VERSION 5.8 ;
BUSBITCHARS "[]" ;
DIVIDERCHAR "/" ;
UNITS
    DATABASE MICRONS 1000 ;
END UNITS

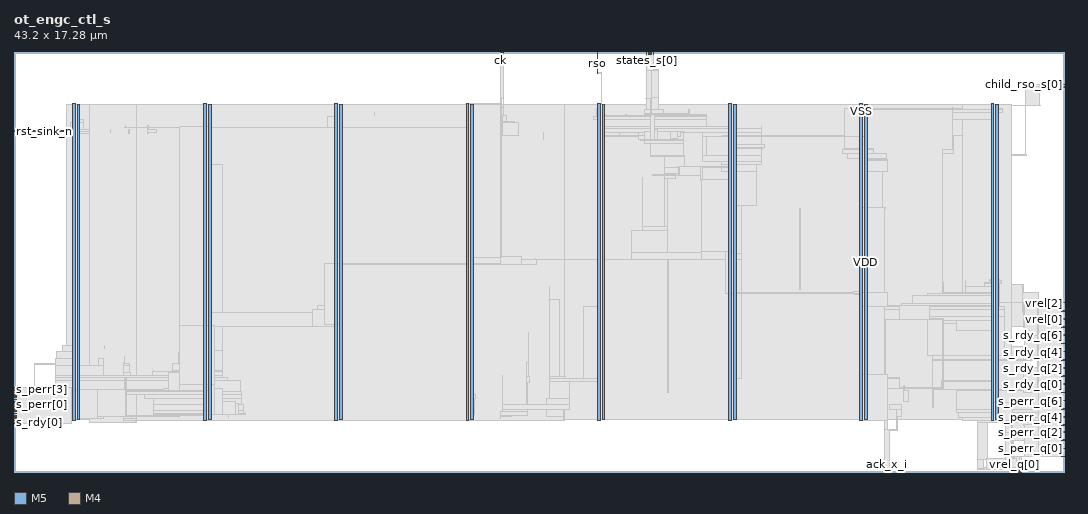
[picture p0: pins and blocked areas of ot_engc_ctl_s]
MACRO ot_engc_ctl_s
  FOREIGN ot_engc_ctl_s 0 0 ;
  CLASS BLOCK ;
  SIZE 43.2 BY 17.28 ;
  PIN ack_x_i
    DIRECTION INPUT ;
    USE SIGNAL ;
    PORT
      LAYER M5 ;
        RECT  35.904 0 35.928 0.084 ;
    END
  END ack_x_i
  PIN child_rso_s[0]
    DIRECTION INPUT ;
    USE SIGNAL ;
    PORT
      LAYER M4 ;
        RECT  43.116 15.936 43.2 15.96 ;
    END
  END child_rso_s[0]
  PIN child_rso_s[1]
    DIRECTION INPUT ;
    USE SIGNAL ;
    PORT
      LAYER M5 ;
        RECT  35.808 0 35.832 0.084 ;
    END
  END child_rso_s[1]
  PIN ck
    DIRECTION INPUT ;
    USE SIGNAL ;
    PORT
      LAYER M5 ;
        RECT  20.016 17.196 20.04 17.28 ;
    END
  END ck
  PIN rso
    DIRECTION OUTPUT ;
    USE SIGNAL ;
    PORT
      LAYER M5 ;
        RECT  24 17.196 24.024 17.28 ;
    END
    PORT
      LAYER M5 ;
        RECT  24 16.405 24.024 17.232 ;
    END
  END rso
  PIN rst
    DIRECTION INPUT ;
    USE SIGNAL ;
    PORT
      LAYER M5 ;
        RECT  20.112 17.196 20.136 17.28 ;
    END
  END rst
  PIN rst_lkp_n
    DIRECTION OUTPUT ;
    USE SIGNAL ;
    PORT
      LAYER M5 ;
        RECT  41.04 0 41.064 0.084 ;
    END
  END rst_lkp_n
  PIN rst_sink_n
    DIRECTION OUTPUT ;
    USE SIGNAL ;
    PORT
      LAYER M4 ;
        RECT  0 14.016 0.084 14.04 ;
    END
    PORT
      LAYER M4 ;
        RECT  0.06 14.016 2.408 14.04 ;
    END
  END rst_sink_n
  PIN rst_win_n
    DIRECTION OUTPUT ;
    USE SIGNAL ;
    PORT
      LAYER M4 ;
        RECT  43.116 15.84 43.2 15.864 ;
    END
  END rst_win_n
  PIN rst_ws_n
    DIRECTION OUTPUT ;
    USE SIGNAL ;
    PORT
      LAYER M5 ;
        RECT  36 0 36.024 0.084 ;
    END
  END rst_ws_n
  PIN s_perr[0]
    DIRECTION INPUT ;
    USE SIGNAL ;
    PORT
      LAYER M4 ;
        RECT  0 2.784 0.084 2.808 ;
    END
  END s_perr[0]
  PIN s_perr[1]
    DIRECTION INPUT ;
    USE SIGNAL ;
    PORT
      LAYER M4 ;
        RECT  0 2.88 0.084 2.904 ;
    END
  END s_perr[1]
  PIN s_perr[2]
    DIRECTION INPUT ;
    USE SIGNAL ;
    PORT
      LAYER M4 ;
        RECT  0 2.976 0.084 3 ;
    END
  END s_perr[2]
  PIN s_perr[3]
    DIRECTION INPUT ;
    USE SIGNAL ;
    PORT
      LAYER M4 ;
        RECT  0 3.072 0.084 3.096 ;
    END
  END s_perr[3]
  PIN s_perr[4]
    DIRECTION INPUT ;
    USE SIGNAL ;
    PORT
      LAYER M4 ;
        RECT  0 3.168 0.084 3.192 ;
    END
  END s_perr[4]
  PIN s_perr[5]
    DIRECTION INPUT ;
    USE SIGNAL ;
    PORT
      LAYER M4 ;
        RECT  0 3.264 0.084 3.288 ;
    END
  END s_perr[5]
  PIN s_perr[6]
    DIRECTION INPUT ;
    USE SIGNAL ;
    PORT
      LAYER M4 ;
        RECT  0 3.36 0.084 3.384 ;
    END
  END s_perr[6]
  PIN s_perr[7]
    DIRECTION INPUT ;
    USE SIGNAL ;
    PORT
      LAYER M4 ;
        RECT  0 3.456 0.084 3.48 ;
    END
  END s_perr[7]
  PIN s_perr_q[0]
    DIRECTION OUTPUT ;
    USE SIGNAL ;
    PORT
      LAYER M4 ;
        RECT  43.116 0.624 43.2 0.648 ;
    END
  END s_perr_q[0]
  PIN s_perr_q[1]
    DIRECTION OUTPUT ;
    USE SIGNAL ;
    PORT
      LAYER M4 ;
        RECT  43.116 0.96 43.2 0.984 ;
    END
  END s_perr_q[1]
  PIN s_perr_q[2]
    DIRECTION OUTPUT ;
    USE SIGNAL ;
    PORT
      LAYER M4 ;
        RECT  43.116 1.296 43.2 1.32 ;
    END
  END s_perr_q[2]
  PIN s_perr_q[3]
    DIRECTION OUTPUT ;
    USE SIGNAL ;
    PORT
      LAYER M4 ;
        RECT  43.116 1.632 43.2 1.656 ;
    END
  END s_perr_q[3]
  PIN s_perr_q[4]
    DIRECTION OUTPUT ;
    USE SIGNAL ;
    PORT
      LAYER M4 ;
        RECT  43.116 1.92 43.2 1.944 ;
    END
  END s_perr_q[4]
  PIN s_perr_q[5]
    DIRECTION OUTPUT ;
    USE SIGNAL ;
    PORT
      LAYER M4 ;
        RECT  43.116 2.256 43.2 2.28 ;
    END
  END s_perr_q[5]
  PIN s_perr_q[6]
    DIRECTION OUTPUT ;
    USE SIGNAL ;
    PORT
      LAYER M4 ;
        RECT  43.116 2.592 43.2 2.616 ;
    END
  END s_perr_q[6]
  PIN s_perr_q[7]
    DIRECTION OUTPUT ;
    USE SIGNAL ;
    PORT
      LAYER M4 ;
        RECT  43.116 2.928 43.2 2.952 ;
    END
  END s_perr_q[7]
  PIN s_rdy[0]
    DIRECTION INPUT ;
    USE SIGNAL ;
    PORT
      LAYER M4 ;
        RECT  0 2.016 0.084 2.04 ;
    END
  END s_rdy[0]
  PIN s_rdy[1]
    DIRECTION INPUT ;
    USE SIGNAL ;
    PORT
      LAYER M4 ;
        RECT  0 2.112 0.084 2.136 ;
    END
  END s_rdy[1]
  PIN s_rdy[2]
    DIRECTION INPUT ;
    USE SIGNAL ;
    PORT
      LAYER M4 ;
        RECT  0 2.208 0.084 2.232 ;
    END
  END s_rdy[2]
  PIN s_rdy[3]
    DIRECTION INPUT ;
    USE SIGNAL ;
    PORT
      LAYER M4 ;
        RECT  0 2.304 0.084 2.328 ;
    END
  END s_rdy[3]
  PIN s_rdy[4]
    DIRECTION INPUT ;
    USE SIGNAL ;
    PORT
      LAYER M4 ;
        RECT  0 2.4 0.084 2.424 ;
    END
  END s_rdy[4]
  PIN s_rdy[5]
    DIRECTION INPUT ;
    USE SIGNAL ;
    PORT
      LAYER M4 ;
        RECT  0 2.496 0.084 2.52 ;
    END
  END s_rdy[5]
  PIN s_rdy[6]
    DIRECTION INPUT ;
    USE SIGNAL ;
    PORT
      LAYER M4 ;
        RECT  0 2.592 0.084 2.616 ;
    END
  END s_rdy[6]
  PIN s_rdy[7]
    DIRECTION INPUT ;
    USE SIGNAL ;
    PORT
      LAYER M4 ;
        RECT  0 2.688 0.084 2.712 ;
    END
  END s_rdy[7]
  PIN s_rdy_q[0]
    DIRECTION OUTPUT ;
    USE SIGNAL ;
    PORT
      LAYER M4 ;
        RECT  43.116 3.264 43.2 3.288 ;
    END
  END s_rdy_q[0]
  PIN s_rdy_q[1]
    DIRECTION OUTPUT ;
    USE SIGNAL ;
    PORT
      LAYER M4 ;
        RECT  43.116 3.6 43.2 3.624 ;
    END
  END s_rdy_q[1]
  PIN s_rdy_q[2]
    DIRECTION OUTPUT ;
    USE SIGNAL ;
    PORT
      LAYER M4 ;
        RECT  43.116 3.936 43.2 3.96 ;
    END
  END s_rdy_q[2]
  PIN s_rdy_q[3]
    DIRECTION OUTPUT ;
    USE SIGNAL ;
    PORT
      LAYER M4 ;
        RECT  43.116 4.272 43.2 4.296 ;
    END
  END s_rdy_q[3]
  PIN s_rdy_q[4]
    DIRECTION OUTPUT ;
    USE SIGNAL ;
    PORT
      LAYER M4 ;
        RECT  43.116 4.608 43.2 4.632 ;
    END
  END s_rdy_q[4]
  PIN s_rdy_q[5]
    DIRECTION OUTPUT ;
    USE SIGNAL ;
    PORT
      LAYER M4 ;
        RECT  43.116 4.944 43.2 4.968 ;
    END
  END s_rdy_q[5]
  PIN s_rdy_q[6]
    DIRECTION OUTPUT ;
    USE SIGNAL ;
    PORT
      LAYER M4 ;
        RECT  43.116 5.28 43.2 5.304 ;
    END
  END s_rdy_q[6]
  PIN s_rdy_q[7]
    DIRECTION OUTPUT ;
    USE SIGNAL ;
    PORT
      LAYER M4 ;
        RECT  43.116 5.616 43.2 5.64 ;
    END
  END s_rdy_q[7]
  PIN states_s[0]
    DIRECTION OUTPUT ;
    USE SIGNAL ;
    PORT
      LAYER M5 ;
        RECT  26.016 17.196 26.04 17.28 ;
    END
  END states_s[0]
  PIN states_s[1]
    DIRECTION OUTPUT ;
    USE SIGNAL ;
    PORT
      LAYER M5 ;
        RECT  26.112 17.196 26.136 17.28 ;
    END
  END states_s[1]
  PIN states_s[2]
    DIRECTION OUTPUT ;
    USE SIGNAL ;
    PORT
      LAYER M5 ;
        RECT  26.208 17.196 26.232 17.28 ;
    END
  END states_s[2]
  PIN states_s[3]
    DIRECTION OUTPUT ;
    USE SIGNAL ;
    PORT
      LAYER M5 ;
        RECT  26.304 17.196 26.328 17.28 ;
    END
  END states_s[3]
  PIN vrel[0]
    DIRECTION INPUT ;
    USE SIGNAL ;
    PORT
      LAYER M4 ;
        RECT  43.116 5.952 43.2 5.976 ;
    END
  END vrel[0]
  PIN vrel[1]
    DIRECTION INPUT ;
    USE SIGNAL ;
    PORT
      LAYER M4 ;
        RECT  43.116 6.288 43.2 6.312 ;
    END
  END vrel[1]
  PIN vrel[2]
    DIRECTION INPUT ;
    USE SIGNAL ;
    PORT
      LAYER M4 ;
        RECT  43.116 6.624 43.2 6.648 ;
    END
  END vrel[2]
  PIN vrel[3]
    DIRECTION INPUT ;
    USE SIGNAL ;
    PORT
      LAYER M4 ;
        RECT  43.116 6.96 43.2 6.984 ;
    END
  END vrel[3]
  PIN vrel_q[0]
    DIRECTION OUTPUT ;
    USE SIGNAL ;
    PORT
      LAYER M5 ;
        RECT  41.136 0 41.16 0.084 ;
    END
  END vrel_q[0]
  PIN vrel_q[1]
    DIRECTION OUTPUT ;
    USE SIGNAL ;
    PORT
      LAYER M5 ;
        RECT  41.232 0 41.256 0.084 ;
    END
  END vrel_q[1]
  PIN vrel_q[2]
    DIRECTION OUTPUT ;
    USE SIGNAL ;
    PORT
      LAYER M5 ;
        RECT  41.328 0 41.352 0.084 ;
    END
  END vrel_q[2]
  PIN vrel_q[3]
    DIRECTION OUTPUT ;
    USE SIGNAL ;
    PORT
      LAYER M5 ;
        RECT  41.424 0 41.448 0.084 ;
    END
  END vrel_q[3]
  PIN VDD
    DIRECTION INOUT ;
    USE POWER ;
    PORT
      LAYER M5 ;
        RECT  40.392 2.151 40.512 15.129 ;
        RECT  34.992 2.151 35.112 15.129 ;
        RECT  29.592 2.151 29.712 15.129 ;
        RECT  24.192 2.151 24.312 15.129 ;
        RECT  18.792 2.151 18.912 15.129 ;
        RECT  13.392 2.151 13.512 15.129 ;
        RECT  7.992 2.151 8.112 15.129 ;
        RECT  2.592 2.151 2.712 15.129 ;
    END
  END VDD
  PIN VSS
    DIRECTION INOUT ;
    USE GROUND ;
    PORT
      LAYER M5 ;
        RECT  40.2 2.137 40.32 15.143 ;
        RECT  34.8 2.137 34.92 15.143 ;
        RECT  29.4 2.137 29.52 15.143 ;
        RECT  24 2.137 24.12 15.143 ;
        RECT  18.6 2.137 18.72 15.143 ;
        RECT  13.2 2.137 13.32 15.143 ;
        RECT  7.8 2.137 7.92 15.143 ;
        RECT  2.4 2.137 2.52 15.143 ;
    END
  END VSS
  # OT_OBS_CLOSED layer=M5 d_um=1.536 added=5
  OBS
    LAYER RVTN ;
     RECT  2.16 2.16 41.04 2.295 ;
     RECT  2.16 2.565 41.04 2.835 ;
     RECT  2.16 3.105 41.04 3.375 ;
     RECT  2.16 3.645 41.04 3.915 ;
     RECT  2.16 4.185 41.04 4.455 ;
     RECT  2.16 4.725 41.04 4.995 ;
     RECT  2.16 5.265 41.04 5.535 ;
     RECT  2.16 5.805 41.04 6.075 ;
     RECT  2.16 6.345 41.04 6.615 ;
     RECT  2.16 6.885 41.04 7.155 ;
     RECT  2.16 7.425 41.04 7.695 ;
     RECT  2.16 7.965 41.04 8.235 ;
     RECT  2.16 8.505 41.04 8.775 ;
     RECT  2.16 9.045 41.04 9.315 ;
     RECT  2.16 9.585 41.04 9.855 ;
     RECT  2.16 10.125 41.04 10.395 ;
     RECT  2.16 10.665 41.04 10.935 ;
     RECT  2.16 11.205 41.04 11.475 ;
     RECT  2.16 11.745 41.04 12.015 ;
     RECT  2.16 12.285 41.04 12.555 ;
     RECT  2.16 12.825 41.04 13.095 ;
     RECT  2.16 13.365 41.04 13.635 ;
     RECT  2.16 13.905 41.04 14.175 ;
     RECT  2.16 14.445 41.04 14.715 ;
     RECT  2.16 14.985 41.04 15.12 ;
    LAYER RVTP ;
     RECT  2.16 2.295 41.04 2.565 ;
     RECT  2.16 2.835 41.04 3.105 ;
     RECT  2.16 3.375 41.04 3.645 ;
     RECT  2.16 3.915 41.04 4.185 ;
     RECT  2.16 4.455 41.04 4.725 ;
     RECT  2.16 4.995 41.04 5.265 ;
     RECT  2.16 5.535 41.04 5.805 ;
     RECT  2.16 6.075 41.04 6.345 ;
     RECT  2.16 6.615 41.04 6.885 ;
     RECT  2.16 7.155 41.04 7.425 ;
     RECT  2.16 7.695 41.04 7.965 ;
     RECT  2.16 8.235 41.04 8.505 ;
     RECT  2.16 8.775 41.04 9.045 ;
     RECT  2.16 9.315 41.04 9.585 ;
     RECT  2.16 9.855 41.04 10.125 ;
     RECT  2.16 10.395 41.04 10.665 ;
     RECT  2.16 10.935 41.04 11.205 ;
     RECT  2.16 11.475 41.04 11.745 ;
     RECT  2.16 12.015 41.04 12.285 ;
     RECT  2.16 12.555 41.04 12.825 ;
     RECT  2.16 13.095 41.04 13.365 ;
     RECT  2.16 13.635 41.04 13.905 ;
     RECT  2.16 14.175 41.04 14.445 ;
     RECT  2.16 14.715 41.04 14.985 ;
    LAYER M1 ;
     RECT  2.16 2.151 41.04 15.129 ;
    LAYER M2 ;
     RECT  0.823 4.428 1.723 4.446 ;
     RECT  1.723 4.428 1.759 4.68 ;
     RECT  1.759 4.428 1.975 4.95 ;
     RECT  1.975 4.428 2.16 5.22 ;
     RECT  2.16 2.151 3.091 15.129 ;
     RECT  3.091 2.034 5.027 15.129 ;
     RECT  5.027 2.106 22.631 15.129 ;
     RECT  22.631 2.151 39.019 15.129 ;
     RECT  39.019 2.106 40.387 15.129 ;
     RECT  40.387 2.034 41.04 15.129 ;
     RECT  41.04 5.976 41.531 7.722 ;
     RECT  41.04 2.034 41.567 5.184 ;
     RECT  41.567 2.034 41.603 3.366 ;
     RECT  41.567 4.896 41.603 5.184 ;
     RECT  41.531 5.976 41.603 7.38 ;
     RECT  41.04 13.032 41.639 13.05 ;
     RECT  41.603 5.976 42.143 6.534 ;
     RECT  41.603 7.362 42.143 7.38 ;
     RECT  41.603 2.268 42.179 3.366 ;
     RECT  41.603 5.166 42.179 5.184 ;
     RECT  42.143 6.516 42.179 6.534 ;
     RECT  42.179 3.348 42.215 3.366 ;
     RECT  41.04 15.066 42.215 15.084 ;
     RECT  42.179 2.538 42.251 2.556 ;
    LAYER M3 ;
     RECT  39.636 0.091 39.654 0.139 ;
     RECT  39.636 0.139 39.906 0.523 ;
     RECT  41.112 0.571 41.13 0.619 ;
     RECT  40.788 0.619 41.13 1.291 ;
     RECT  42.192 0.955 42.21 1.291 ;
     RECT  40.788 1.291 42.21 1.627 ;
     RECT  39.636 0.523 40.05 2.029 ;
     RECT  40.788 1.627 42.246 2.029 ;
     RECT  5.004 2.029 5.022 2.101 ;
     RECT  39.636 2.029 42.246 2.101 ;
     RECT  2.34 2.011 2.358 2.107 ;
     RECT  2.304 2.107 2.358 2.143 ;
     RECT  3.096 2.029 3.114 2.143 ;
     RECT  2.304 2.143 3.114 2.191 ;
     RECT  34.815 2.143 34.905 2.191 ;
     RECT  2.304 2.191 3.69 2.203 ;
     RECT  4.5 2.101 5.022 2.219 ;
     RECT  39.024 2.101 42.246 2.227 ;
     RECT  22.608 2.101 22.626 2.263 ;
     RECT  36.324 1.723 36.342 2.263 ;
     RECT  2.268 2.203 3.69 2.299 ;
     RECT  4.5 2.219 4.842 2.299 ;
     RECT  6.804 2.227 6.822 2.299 ;
     RECT  20.016 2.191 20.034 2.299 ;
     RECT  2.268 2.299 4.842 2.333 ;
     RECT  5.724 2.299 6.822 2.335 ;
     RECT  7.815 2.143 7.905 2.335 ;
     RECT  20.016 2.299 20.466 2.335 ;
     RECT  5.724 2.335 7.905 2.347 ;
     RECT  8.82 2.227 8.838 2.347 ;
     RECT  18.615 2.143 18.705 2.371 ;
     RECT  8.82 2.347 9.522 2.399 ;
     RECT  5.724 2.347 7.974 2.413 ;
     RECT  13.215 2.143 13.305 2.413 ;
     RECT  24.015 2.143 24.105 2.413 ;
     RECT  29.415 2.143 29.505 2.413 ;
     RECT  34.776 2.191 34.905 2.413 ;
     RECT  38.844 2.227 42.246 2.461 ;
     RECT  20.016 2.335 21.114 2.489 ;
     RECT  5.724 2.413 8.097 2.533 ;
     RECT  8.82 2.399 9.45 2.533 ;
     RECT  38.772 2.461 42.246 2.561 ;
     RECT  20.088 2.489 21.114 2.569 ;
     RECT  21.924 2.263 22.626 2.569 ;
     RECT  36.324 2.263 36.522 2.569 ;
     RECT  34.776 2.413 35.097 2.633 ;
     RECT  2.268 2.333 4.194 2.683 ;
     RECT  5.724 2.533 9.45 2.759 ;
     RECT  20.088 2.569 22.842 2.759 ;
     RECT  36.036 2.569 36.522 2.795 ;
     RECT  1.98 2.683 4.194 2.971 ;
     RECT  21.924 2.759 22.842 3.029 ;
     RECT  5.724 2.759 9.342 3.037 ;
     RECT  18.615 2.371 18.954 3.037 ;
     RECT  1.728 2.971 4.194 3.181 ;
     RECT  5.364 3.037 9.342 3.181 ;
     RECT  18.615 3.037 18.99 3.209 ;
     RECT  1.728 3.181 9.342 3.299 ;
     RECT  36.612 2.911 36.81 3.335 ;
     RECT  38.772 2.561 42.21 3.371 ;
     RECT  37.8 2.641 37.818 3.379 ;
     RECT  38.772 3.371 41.598 3.379 ;
     RECT  34.815 2.633 35.097 3.451 ;
     RECT  36.612 3.335 36.63 3.569 ;
     RECT  34.815 3.451 35.37 3.577 ;
     RECT  21.096 2.759 21.114 3.685 ;
     RECT  22.032 3.029 22.842 3.721 ;
     RECT  24.015 2.413 24.297 3.721 ;
     RECT  34.815 3.577 36.414 3.721 ;
     RECT  1.728 3.299 9.306 3.749 ;
     RECT  22.032 3.721 24.297 3.839 ;
     RECT  29.415 2.413 29.697 3.847 ;
     RECT  34.776 3.721 36.414 3.869 ;
     RECT  1.728 3.749 8.802 3.875 ;
     RECT  34.776 3.869 36.342 3.875 ;
     RECT  21.096 3.685 21.222 3.911 ;
     RECT  22.032 3.839 22.698 3.947 ;
     RECT  34.776 3.875 35.838 3.947 ;
     RECT  1.728 3.875 8.586 3.983 ;
     RECT  20.088 2.759 20.106 3.983 ;
     RECT  4.5 3.983 4.806 4.109 ;
     RECT  5.688 3.983 8.586 4.115 ;
     RECT  5.688 4.115 5.742 4.145 ;
     RECT  5.724 4.145 5.742 4.181 ;
     RECT  6.516 4.115 8.586 4.181 ;
     RECT  1.728 3.983 3.69 4.379 ;
     RECT  4.5 4.109 4.77 4.379 ;
     RECT  0.828 2.491 0.846 4.451 ;
     RECT  4.5 4.379 4.734 4.451 ;
     RECT  6.516 4.181 6.822 4.451 ;
     RECT  4.5 4.451 4.554 4.487 ;
     RECT  21.096 3.911 21.186 4.487 ;
     RECT  37.8 3.379 41.598 4.603 ;
     RECT  37.8 4.603 42.174 4.649 ;
     RECT  1.728 4.379 2.697 4.685 ;
     RECT  3.492 4.379 3.69 4.685 ;
     RECT  4.536 4.487 4.554 4.757 ;
     RECT  41.544 4.649 42.174 4.757 ;
     RECT  37.8 4.649 40.77 4.801 ;
     RECT  6.768 4.451 6.822 4.919 ;
     RECT  1.764 4.685 2.697 4.955 ;
     RECT  7.56 4.181 8.586 4.991 ;
     RECT  6.804 4.919 6.822 5.063 ;
     RECT  3.708 5.071 3.726 5.189 ;
     RECT  1.98 4.955 2.697 5.225 ;
     RECT  21.168 4.487 21.186 5.729 ;
     RECT  41.58 4.757 42.174 5.947 ;
     RECT  13.215 2.413 13.497 5.971 ;
     RECT  12.852 5.971 13.497 6.079 ;
     RECT  34.815 3.947 35.838 6.283 ;
     RECT  37.584 4.801 40.77 6.385 ;
     RECT  12.672 6.079 13.497 6.511 ;
     RECT  41.544 5.947 42.174 6.539 ;
     RECT  41.544 6.539 42.138 6.619 ;
     RECT  12.492 6.511 13.497 6.655 ;
     RECT  34.815 6.283 36.45 6.691 ;
     RECT  37.224 6.385 40.77 6.691 ;
     RECT  12.276 6.655 13.497 6.701 ;
     RECT  23.436 3.839 24.297 6.809 ;
     RECT  34.815 6.691 40.77 6.809 ;
     RECT  12.492 6.701 13.497 6.845 ;
     RECT  34.815 6.809 40.554 6.845 ;
     RECT  36.504 6.845 40.554 6.917 ;
     RECT  41.508 6.619 42.138 6.955 ;
     RECT  22.032 3.947 22.446 7.079 ;
     RECT  34.815 6.845 35.73 7.159 ;
     RECT  36.972 6.917 40.554 7.259 ;
     RECT  34.812 7.159 35.73 7.321 ;
     RECT  37.584 7.259 40.554 7.349 ;
     RECT  38.196 7.349 40.554 7.385 ;
     RECT  41.472 6.955 42.138 7.385 ;
     RECT  34.56 7.321 35.73 7.421 ;
     RECT  22.032 7.079 22.05 7.619 ;
     RECT  39.132 7.385 40.554 7.619 ;
     RECT  41.472 7.385 41.526 7.691 ;
     RECT  41.508 7.691 41.526 7.727 ;
     RECT  39.924 7.619 40.554 7.771 ;
     RECT  38.196 7.385 38.25 7.799 ;
     RECT  39.924 7.771 40.626 7.799 ;
     RECT  39.132 7.619 39.15 7.889 ;
     RECT  40.14 7.799 40.626 7.889 ;
     RECT  40.14 7.889 40.554 7.925 ;
     RECT  29.415 3.847 29.934 8.731 ;
     RECT  21.456 8.539 21.474 8.765 ;
     RECT  26.892 3.271 26.91 8.851 ;
     RECT  20.844 8.815 20.862 8.861 ;
     RECT  25.56 8.851 26.91 8.969 ;
     RECT  25.56 8.969 26.874 8.977 ;
     RECT  29.34 8.731 29.934 9.005 ;
     RECT  25.416 8.977 26.874 9.923 ;
     RECT  25.848 9.923 26.874 10.085 ;
     RECT  32.328 7.501 32.346 10.859 ;
     RECT  29.415 9.005 29.934 10.975 ;
     RECT  26.748 10.085 26.874 12.091 ;
     RECT  25.848 10.085 25.866 12.119 ;
     RECT  26.748 12.091 27.234 12.187 ;
     RECT  26.28 12.187 27.234 12.245 ;
     RECT  26.748 12.245 27.234 12.289 ;
     RECT  28.26 11.995 28.278 12.289 ;
     RECT  29.415 10.975 30.546 12.361 ;
     RECT  34.815 7.421 35.73 12.361 ;
     RECT  26.748 12.289 28.278 12.515 ;
     RECT  29.088 12.361 30.546 12.631 ;
     RECT  7.815 4.991 8.586 12.659 ;
     RECT  29.088 12.631 30.762 12.793 ;
     RECT  34.815 12.361 35.946 12.829 ;
     RECT  34.776 12.829 35.946 12.857 ;
     RECT  34.776 12.857 35.91 12.901 ;
     RECT  26.748 12.515 27.594 12.991 ;
     RECT  26.208 12.991 27.594 13.019 ;
     RECT  28.332 12.793 30.762 13.019 ;
     RECT  34.308 12.901 35.91 13.091 ;
     RECT  34.308 13.091 35.37 13.099 ;
     RECT  38.196 7.799 38.214 13.099 ;
     RECT  34.092 13.099 35.37 13.289 ;
     RECT  38.196 13.099 38.646 13.289 ;
     RECT  29.415 13.019 30.762 13.297 ;
     RECT  34.164 13.289 35.37 13.325 ;
     RECT  29.415 13.297 30.798 13.333 ;
     RECT  29.415 13.333 30.87 13.469 ;
     RECT  26.208 13.019 27.558 13.531 ;
     RECT  25.956 13.531 27.558 13.639 ;
     RECT  25.776 13.639 27.558 13.675 ;
     RECT  28.332 13.019 28.494 13.801 ;
     RECT  29.415 13.469 30.762 13.801 ;
     RECT  24.015 6.809 24.297 13.819 ;
     RECT  24.015 13.819 24.498 13.837 ;
     RECT  38.628 13.289 38.646 13.837 ;
     RECT  34.164 13.325 35.097 13.853 ;
     RECT  2.415 5.225 2.697 13.945 ;
     RECT  25.704 13.675 27.558 13.963 ;
     RECT  21.78 13.675 21.798 13.973 ;
     RECT  5.508 13.945 5.526 13.981 ;
     RECT  24.015 13.837 24.894 13.981 ;
     RECT  25.704 13.963 27.594 13.981 ;
     RECT  28.332 13.801 30.762 13.981 ;
     RECT  2.415 13.945 3.114 14.011 ;
     RECT  2.304 14.011 3.114 14.099 ;
     RECT  3.96 13.981 3.978 14.099 ;
     RECT  4.716 13.909 4.734 14.099 ;
     RECT  5.508 13.981 5.85 14.099 ;
     RECT  24.015 13.981 30.762 14.135 ;
     RECT  18.615 3.209 18.897 14.143 ;
     RECT  13.215 6.845 13.497 14.179 ;
     RECT  24.015 14.135 29.697 14.207 ;
     RECT  30.744 14.135 30.762 14.207 ;
     RECT  4.572 14.155 4.59 14.243 ;
     RECT  5.508 14.099 5.526 14.243 ;
     RECT  2.304 14.099 2.862 14.369 ;
     RECT  20.088 13.837 20.754 14.369 ;
     RECT  20.088 14.369 20.61 14.405 ;
     RECT  38.628 13.837 39.042 14.485 ;
     RECT  40.215 7.925 40.497 14.485 ;
     RECT  2.415 14.369 2.862 14.513 ;
     RECT  24.015 14.207 28.494 14.521 ;
     RECT  12.888 14.179 13.497 14.639 ;
     RECT  23.832 14.521 28.494 14.639 ;
     RECT  18.615 14.143 19.314 14.647 ;
     RECT  20.088 14.405 20.25 14.647 ;
     RECT  18.615 14.647 20.25 14.675 ;
     RECT  23.976 14.639 28.494 14.675 ;
     RECT  23.976 14.675 24.354 14.711 ;
     RECT  25.164 14.675 25.182 14.711 ;
     RECT  25.92 14.675 28.494 14.711 ;
     RECT  25.92 14.711 27.774 14.747 ;
     RECT  14.832 14.647 14.85 14.783 ;
     RECT  38.628 14.485 40.497 14.791 ;
     RECT  2.415 14.513 2.697 14.867 ;
     RECT  7.815 12.659 8.097 14.867 ;
     RECT  13.215 14.639 13.497 14.867 ;
     RECT  23.976 14.711 24.297 14.867 ;
     RECT  29.415 14.207 29.697 14.867 ;
     RECT  34.2 13.853 35.097 14.867 ;
     RECT  25.92 14.747 26.73 14.909 ;
     RECT  27.756 14.747 27.774 14.909 ;
     RECT  38.628 14.791 40.662 14.909 ;
     RECT  38.628 14.909 39.042 14.917 ;
     RECT  23.976 14.867 24.174 14.945 ;
     RECT  34.2 14.867 34.905 14.945 ;
     RECT  38.304 14.917 39.042 14.945 ;
     RECT  40.215 14.909 40.662 14.945 ;
     RECT  38.304 14.945 38.646 14.957 ;
     RECT  38.628 14.957 38.646 14.981 ;
     RECT  18.615 14.675 20.142 15.017 ;
     RECT  41.616 13.027 41.634 15.061 ;
     RECT  34.776 14.945 34.905 15.089 ;
     RECT  2.415 14.867 2.505 15.137 ;
     RECT  7.815 14.867 7.905 15.137 ;
     RECT  13.215 14.867 13.305 15.137 ;
     RECT  18.615 15.017 18.705 15.137 ;
     RECT  24.015 14.945 24.174 15.137 ;
     RECT  29.415 14.867 29.505 15.137 ;
     RECT  34.815 15.089 34.905 15.137 ;
     RECT  40.215 14.945 40.305 15.137 ;
     RECT  20.124 15.017 20.142 15.389 ;
     RECT  26.028 14.909 26.514 15.389 ;
     RECT  41.616 15.061 42.21 15.869 ;
     RECT  41.616 15.869 41.634 15.965 ;
     RECT  24.156 15.137 24.174 16.445 ;
     RECT  26.136 15.389 26.514 16.541 ;
     RECT  26.136 16.541 26.154 17.165 ;
    LAYER M4 ;
     RECT  0.06 2.016 2.369 3.48 ;
     RECT  2.369 2.148 2.408 3.48 ;
     RECT  2.408 2.148 2.512 15.132 ;
     RECT  2.512 2.208 2.704 14.862 ;
     RECT  2.704 2.208 3.443 2.328 ;
     RECT  2.704 3.36 4.556 3.768 ;
     RECT  4.556 3.36 4.643 3.864 ;
     RECT  3.443 2.304 6.113 2.328 ;
     RECT  4.643 3.36 6.145 3.384 ;
     RECT  6.145 3.36 6.361 3.432 ;
     RECT  6.361 3.36 7.808 4.104 ;
     RECT  6.805 6.528 7.808 6.552 ;
     RECT  4.561 14.16 7.808 14.184 ;
     RECT  7.808 2.148 7.912 15.132 ;
     RECT  7.912 2.352 8.104 14.862 ;
     RECT  8.104 2.352 8.243 3.624 ;
     RECT  8.243 2.352 8.597 3.432 ;
     RECT  8.597 2.352 9.101 2.904 ;
     RECT  9.101 2.352 9.245 2.808 ;
     RECT  9.245 2.352 9.533 2.376 ;
     RECT  8.104 6 12.265 6.552 ;
     RECT  12.265 6 13.208 6.696 ;
     RECT  12.757 8.544 13.208 8.568 ;
     RECT  8.104 14.16 13.208 14.184 ;
     RECT  13.208 2.148 13.312 15.132 ;
     RECT  13.312 2.418 13.504 14.862 ;
     RECT  13.504 8.544 18.608 8.568 ;
     RECT  13.504 14.16 18.608 14.184 ;
     RECT  18.608 2.148 18.712 15.132 ;
     RECT  18.712 2.418 18.904 14.862 ;
     RECT  18.904 14.16 19.325 14.184 ;
     RECT  18.904 8.544 20.005 8.568 ;
     RECT  20.069 15.36 20.153 15.384 ;
     RECT  20.005 8.544 20.873 8.856 ;
     RECT  20.873 8.544 21.485 8.76 ;
     RECT  21.485 8.736 24.008 8.76 ;
     RECT  24.008 2.148 24.112 15.132 ;
     RECT  23.989 16.416 24.185 16.44 ;
     RECT  24.112 2.418 24.304 14.862 ;
     RECT  24.304 8.736 25.405 8.76 ;
     RECT  24.304 13.824 25.693 13.848 ;
     RECT  25.693 13.68 25.945 13.848 ;
     RECT  25.973 15.36 26.057 15.384 ;
     RECT  26.081 17.136 26.165 17.16 ;
     RECT  25.945 13.68 26.197 13.992 ;
     RECT  26.197 13.68 26.345 14.712 ;
     RECT  26.345 13.68 26.489 14.088 ;
     RECT  26.293 16.512 26.525 16.536 ;
     RECT  26.489 13.68 26.993 13.992 ;
     RECT  26.993 13.728 27.317 13.992 ;
     RECT  26.269 12.192 27.321 12.216 ;
     RECT  27.317 13.824 27.425 13.992 ;
     RECT  27.425 13.968 27.605 13.992 ;
     RECT  27.321 12.192 28.249 12.552 ;
     RECT  28.249 12 28.333 12.552 ;
     RECT  29.269 7.344 29.408 7.368 ;
     RECT  25.405 8.736 29.408 9.048 ;
     RECT  28.333 12.528 29.408 12.552 ;
     RECT  29.149 13.824 29.408 13.848 ;
     RECT  29.408 2.148 29.512 15.132 ;
     RECT  29.512 2.418 29.704 14.862 ;
     RECT  29.704 7.344 34.549 7.368 ;
     RECT  34.549 7.344 34.808 7.416 ;
     RECT  29.704 13.824 34.808 13.848 ;
     RECT  34.165 14.928 34.808 14.952 ;
     RECT  34.808 2.148 34.912 15.132 ;
     RECT  34.912 2.418 35.104 14.952 ;
     RECT  35.104 6.816 35.633 7.416 ;
     RECT  35.104 10.848 35.843 10.872 ;
     RECT  35.104 3.456 35.939 4.008 ;
     RECT  35.633 6.816 35.939 7.368 ;
     RECT  35.989 1.728 36.353 1.752 ;
     RECT  35.939 6.816 36.421 6.84 ;
     RECT  35.939 3.456 36.425 3.864 ;
     RECT  36.421 6.288 37.649 6.84 ;
     RECT  36.425 3.456 38.149 3.48 ;
     RECT  37.649 6.288 38.197 6.312 ;
     RECT  38.149 3.456 38.243 3.768 ;
     RECT  38.197 6.096 38.243 6.312 ;
     RECT  35.104 14.928 38.333 14.952 ;
     RECT  38.243 6.096 38.761 6.216 ;
     RECT  39.625 0.096 39.877 0.12 ;
     RECT  39.877 0.096 40.021 0.168 ;
     RECT  38.243 3.744 40.208 3.768 ;
     RECT  38.761 5.808 40.208 6.216 ;
     RECT  40.208 2.148 40.312 15.132 ;
     RECT  40.312 2.418 40.504 14.862 ;
     RECT  40.021 0.096 40.777 0.552 ;
     RECT  40.504 2.832 41.075 2.856 ;
     RECT  40.777 0.096 41.363 0.648 ;
     RECT  41.363 0.144 41.459 0.648 ;
     RECT  40.504 6.96 41.497 6.984 ;
     RECT  41.497 6.624 41.533 6.984 ;
     RECT  41.459 0.624 41.569 0.648 ;
     RECT  41.533 1.92 41.569 1.944 ;
     RECT  41.533 5.952 41.569 6.984 ;
     RECT  41.533 3.264 42.109 4.296 ;
     RECT  41.569 5.616 42.109 6.984 ;
     RECT  41.569 0.624 42.145 1.944 ;
     RECT  42.109 3.264 42.145 6.984 ;
     RECT  41.605 15.936 42.181 15.96 ;
     RECT  42.145 0.624 43.164 6.984 ;
     RECT  42.181 15.84 43.164 15.96 ;
    LAYER M5 ;
     RECT  41.04 0.016 41.448 0.179 ;
     RECT  41.04 0.179 41.256 0.563 ;
     RECT  41.04 0.563 41.16 0.611 ;
     RECT  35.808 0.016 36.024 1.763 ;
     RECT  35.808 1.763 35.928 2.137 ;
     RECT  41.04 0.611 41.064 2.137 ;
     RECT  2.4 2.137 2.52 2.151 ;
     RECT  7.8 2.137 7.92 2.151 ;
     RECT  13.2 2.137 13.32 2.151 ;
     RECT  18.6 2.137 18.72 2.151 ;
     RECT  24 2.137 24.12 2.151 ;
     RECT  29.4 2.137 29.52 2.151 ;
     RECT  2.4 2.151 2.712 2.197 ;
     RECT  40.2 2.137 41.064 2.867 ;
     RECT  7.8 2.151 8.112 3.349 ;
     RECT  2.4 2.197 3.432 3.395 ;
     RECT  6.816 3.349 8.112 3.589 ;
     RECT  4.608 2.293 4.632 3.875 ;
     RECT  34.8 2.137 35.928 4.019 ;
     RECT  6.816 3.589 8.232 6.035 ;
     RECT  13.2 2.151 13.512 6.085 ;
     RECT  38.208 3.445 38.232 6.323 ;
     RECT  34.8 4.019 35.832 6.805 ;
     RECT  29.4 2.151 29.712 7.333 ;
     RECT  34.8 6.805 35.928 7.379 ;
     RECT  12.768 6.085 13.512 8.579 ;
     RECT  29.28 7.333 29.712 9.059 ;
     RECT  34.8 7.379 35.832 10.883 ;
     RECT  28.272 8.725 28.296 12.035 ;
     RECT  27.36 12.181 27.384 12.563 ;
     RECT  34.8 10.883 35.112 13.813 ;
     RECT  6.816 6.035 8.112 14.195 ;
     RECT  34.176 13.813 35.112 14.963 ;
     RECT  2.4 3.395 2.712 15.129 ;
     RECT  7.8 14.195 8.112 15.129 ;
     RECT  13.2 8.579 13.512 15.129 ;
     RECT  18.6 2.151 18.912 15.129 ;
     RECT  24 2.151 24.312 15.129 ;
     RECT  29.4 9.059 29.712 15.129 ;
     RECT  34.8 14.963 35.112 15.129 ;
     RECT  40.2 2.867 40.512 15.129 ;
     RECT  2.4 15.129 2.52 15.143 ;
     RECT  7.8 15.129 7.92 15.143 ;
     RECT  13.2 15.129 13.32 15.143 ;
     RECT  18.6 15.129 18.72 15.143 ;
     RECT  24 15.129 24.12 15.143 ;
     RECT  29.4 15.129 29.52 15.143 ;
     RECT  34.8 15.129 34.92 15.143 ;
     RECT  40.2 15.129 40.32 15.143 ;
     RECT  20.016 8.821 20.04 15.349 ;
     RECT  26.208 14.677 26.232 15.349 ;
     RECT  26.016 15.349 26.232 16.501 ;
     RECT  20.016 15.349 20.136 17.232 ;
     RECT  26.016 16.501 26.328 17.232 ;
     RECT  3.432 2.293 4.608 3.395 ;
     RECT  28.296 8.725 29.28 9.059 ;
     RECT  18.912 8.821 20.016 15.129 ;
     RECT  28.296 9.059 29.4 12.035 ;
     RECT  18.72 15.129 20.016 15.143 ;
  END
END ot_engc_ctl_s
END LIBRARY
